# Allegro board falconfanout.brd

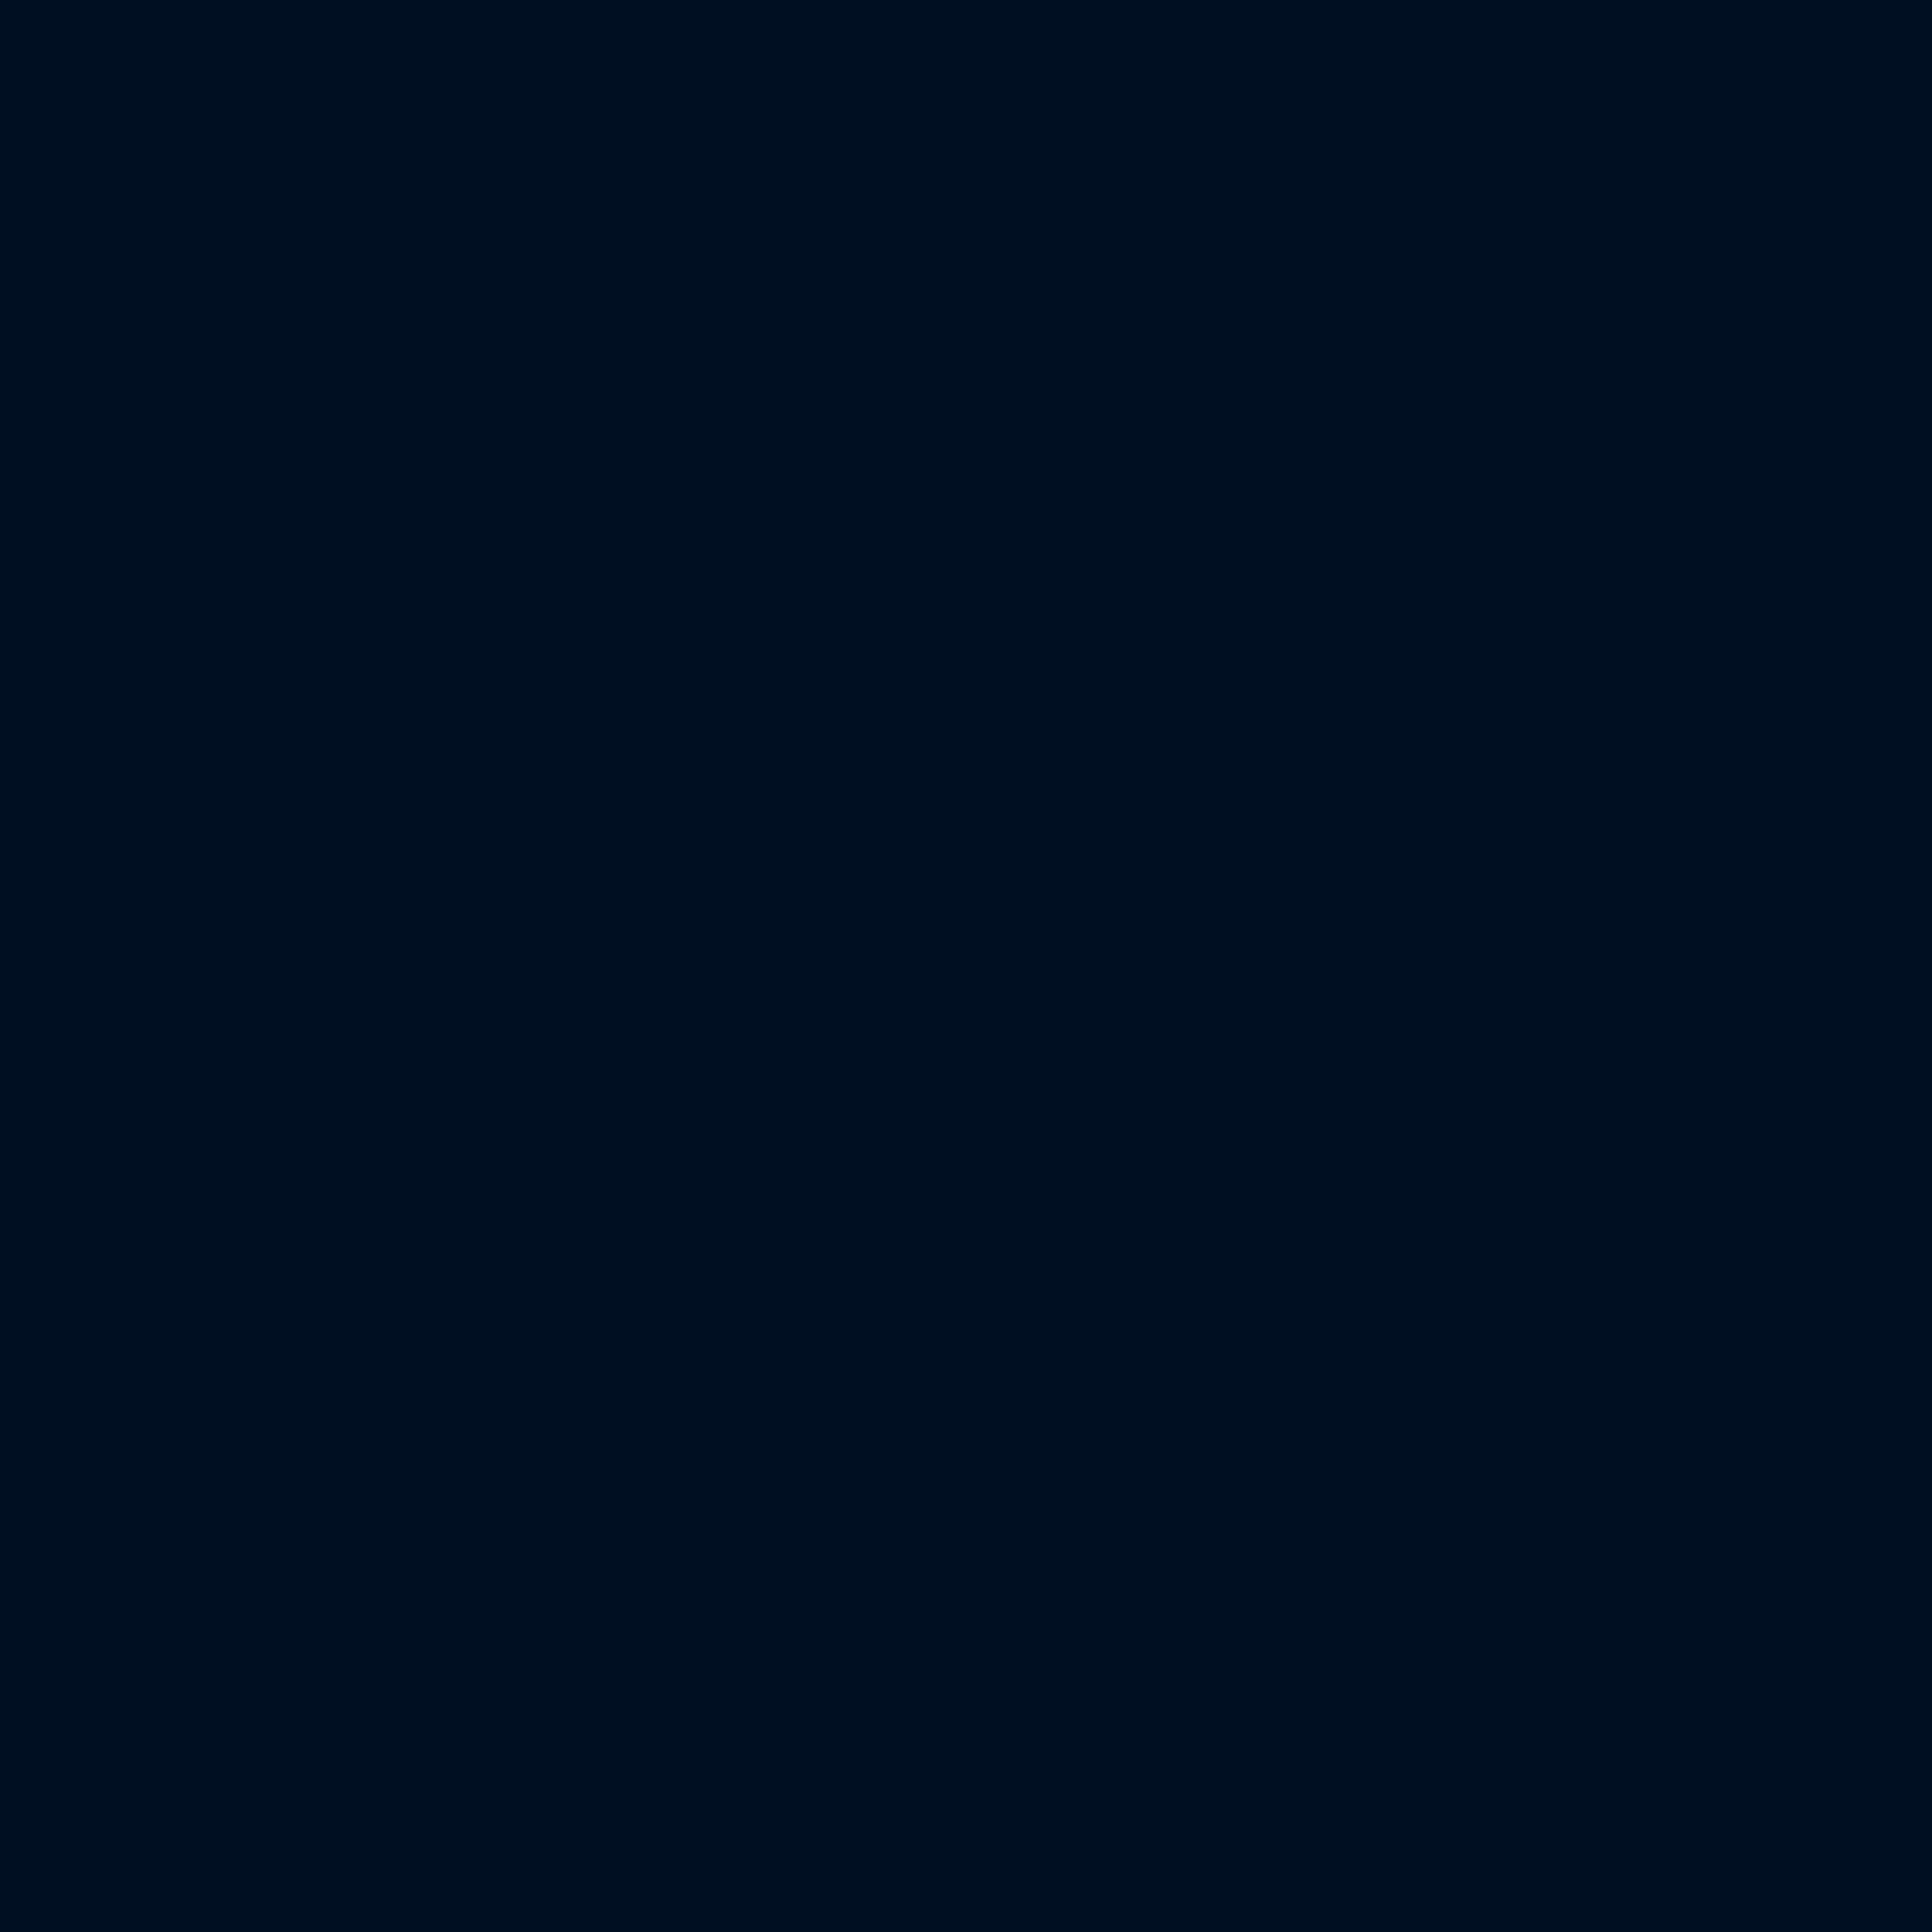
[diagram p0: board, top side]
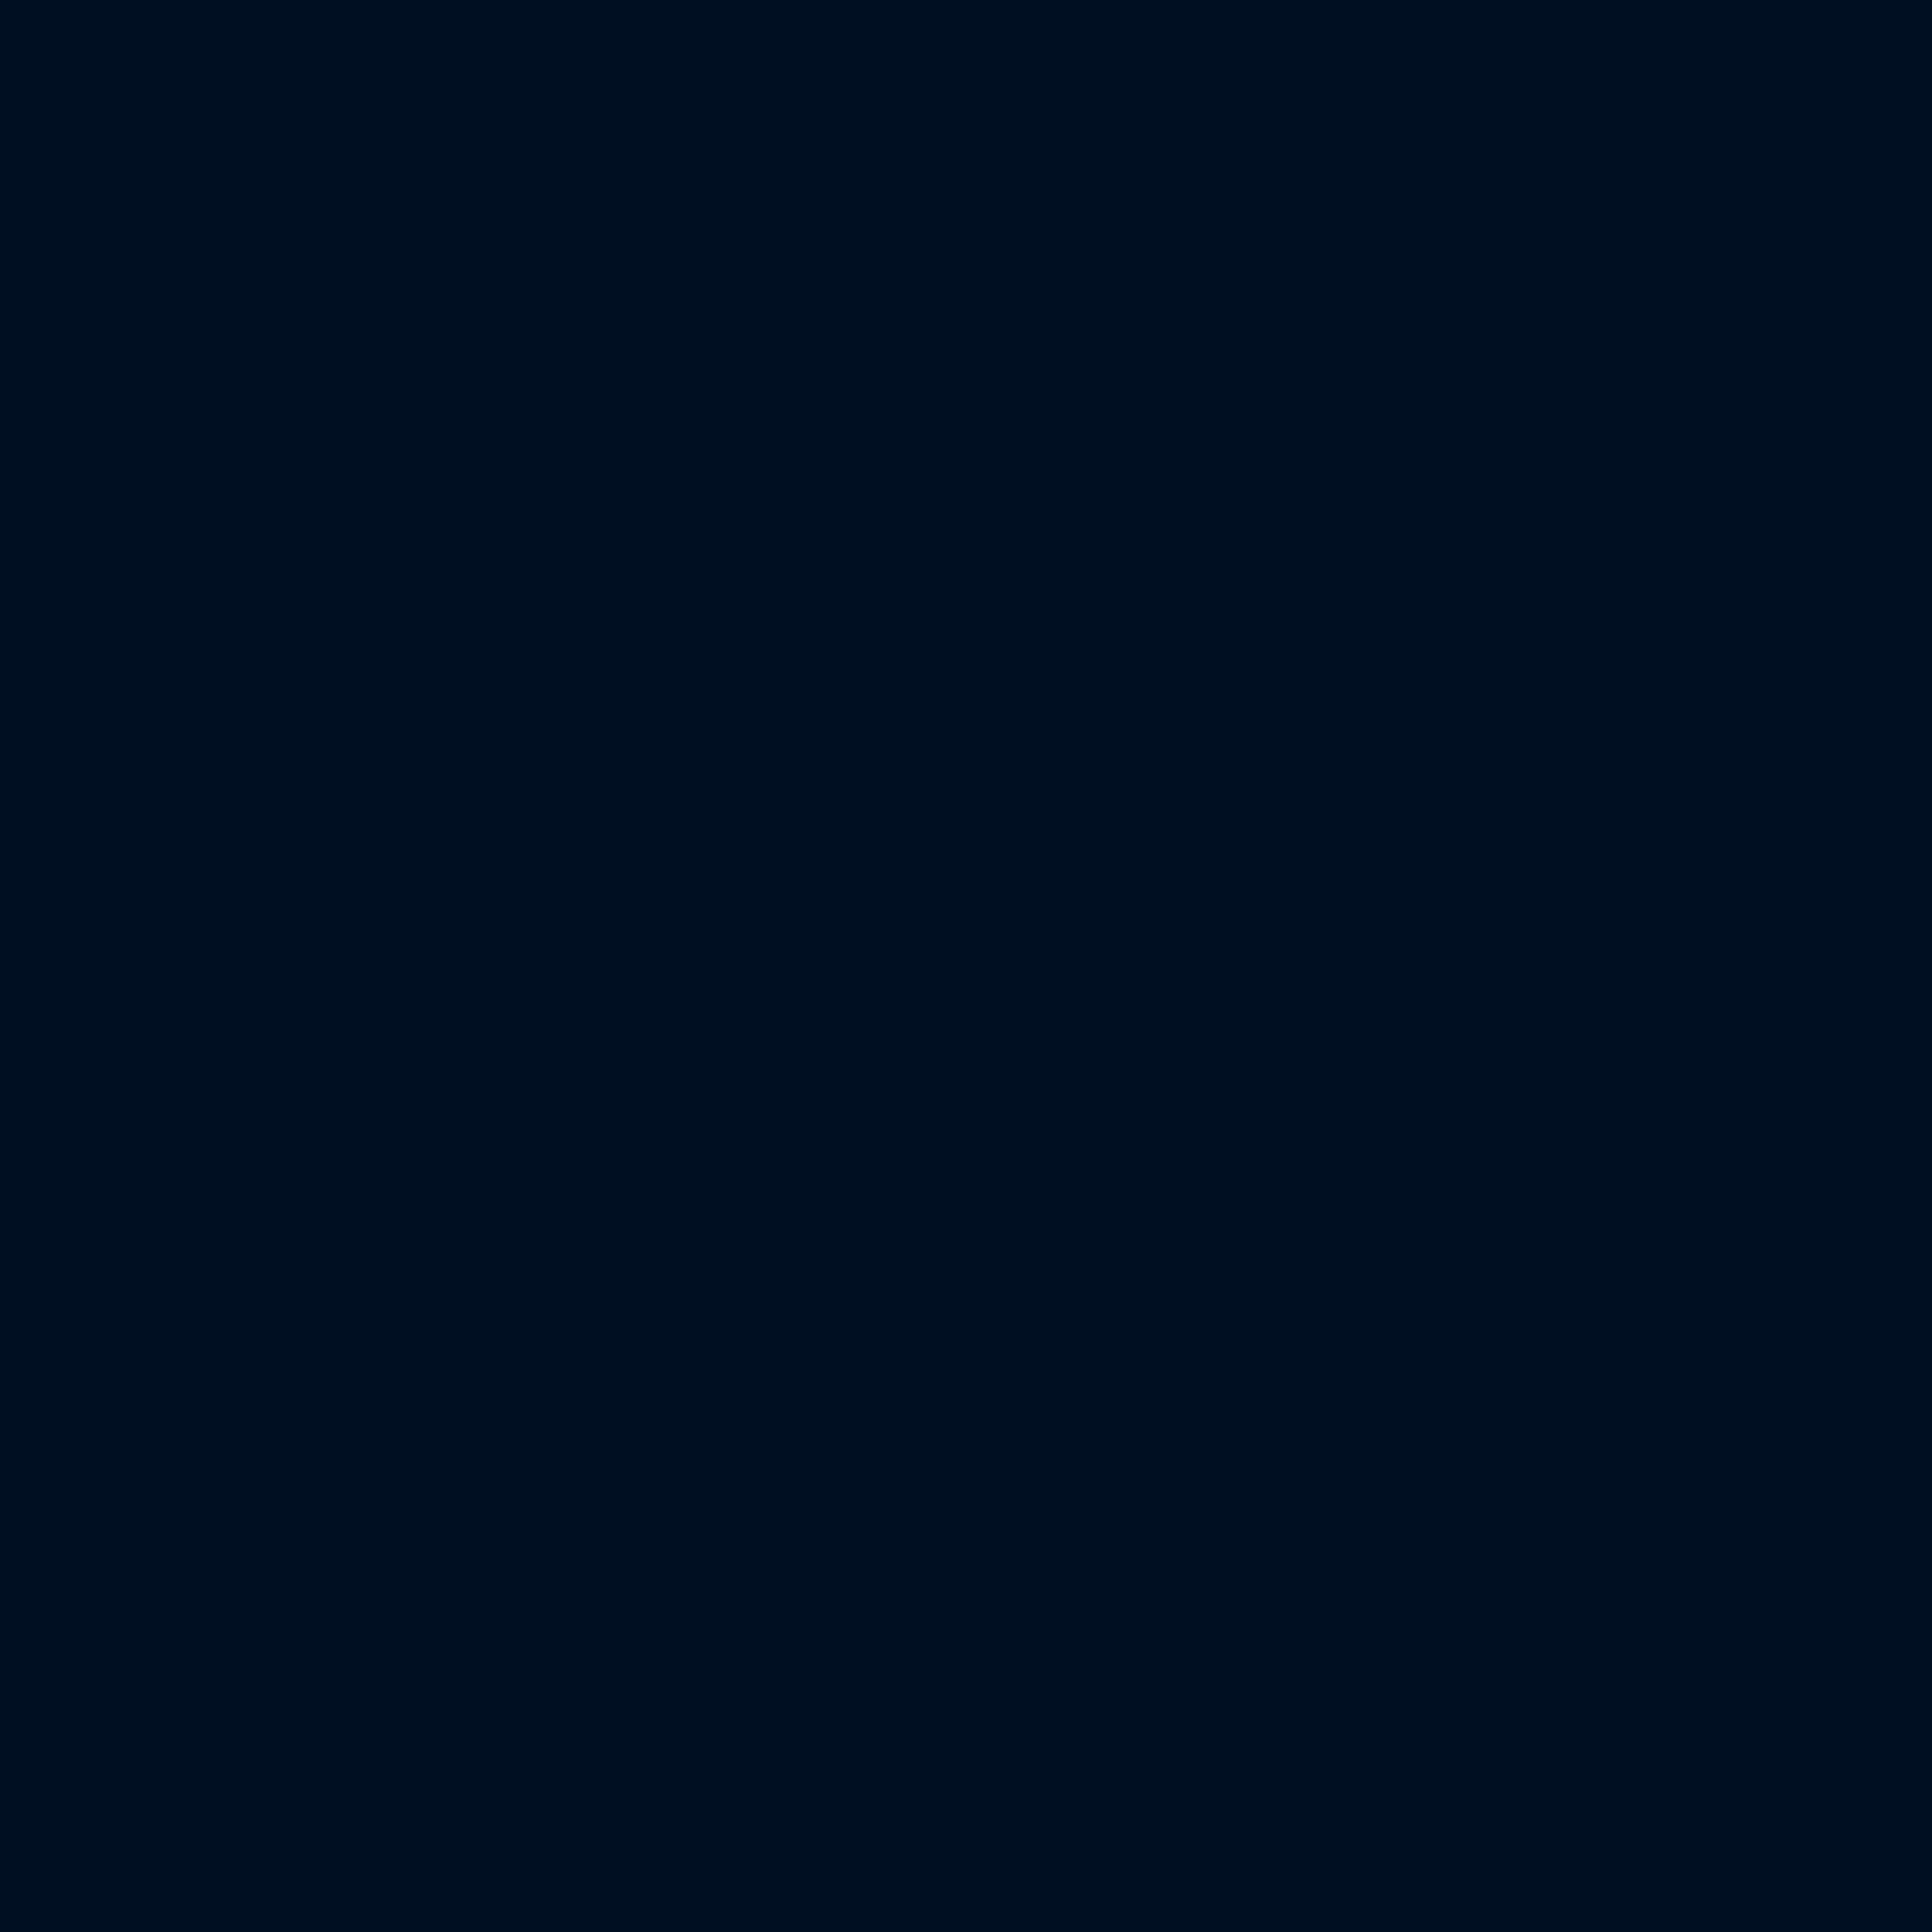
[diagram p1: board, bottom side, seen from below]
No outline. copper layers: TOP, IN1, IN2, BOTTOM. Coordinates in mm from the lowest, leftmost part position.

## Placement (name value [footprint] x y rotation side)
NOREF  -  []  195.58 10.16 0 top
NOREF#2  -  []  0 0 0 top
NOREF#3  -  []  0 0 0 top
NOREF#4  -  []  306.83 109.98 0 top

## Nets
